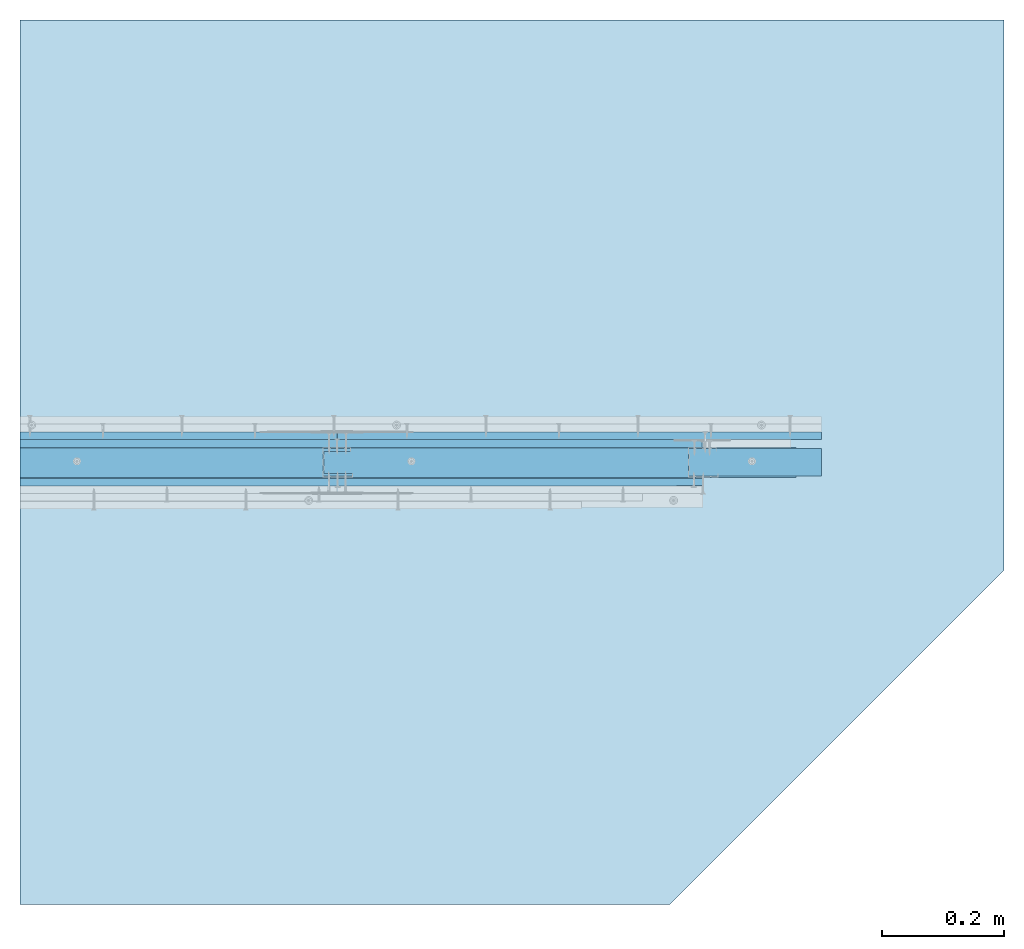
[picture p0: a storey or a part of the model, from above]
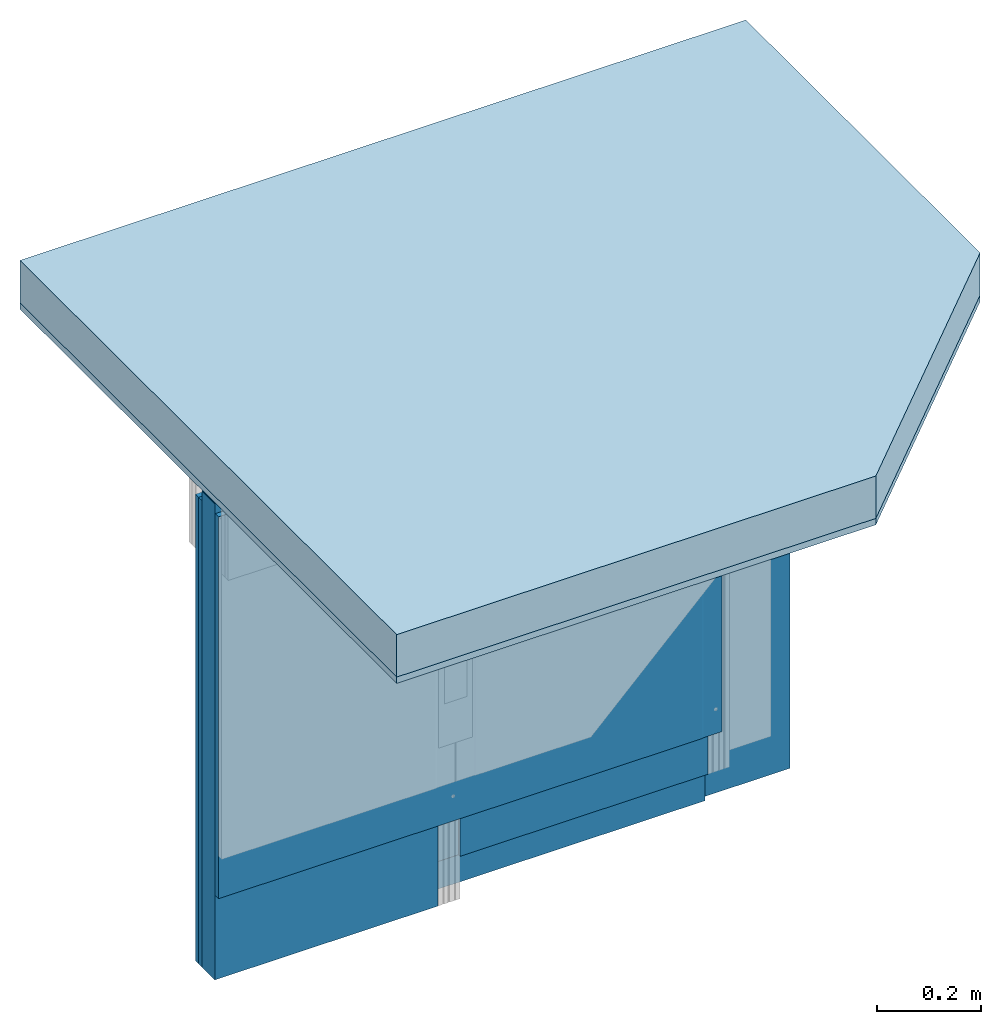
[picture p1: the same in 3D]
Properties of the parts of a building model (IFC2X3)

# File
Description: ViewDefinition [CoordinationView]
Time: 2022-01-07T10:05:12
Made in: SketchUp Pro 2015

# IfcProject, Default Project
Description: Description of Default Project

# IfcSite, Default Site
Description: Description of Default Site; RefLatitude: 24, 28, 0; RefLongitude: 54, 25, 0; RefElevation: 10 mm

# IfcBuilding, Default Building
Description: Description of Default Building

# IfcBuildingStorey, Default Building Storey
In: Default Building
Description: Description of Default Building Storey; Elevation: 0 mm

# IfcSlab (2)
In: Default Building Storey
Description: Description of Object
PredefinedType - IfcSlabTypeEnum: floor
Name
STROP
TYNK

# IfcWall (93)
In: Default Building Storey
Description: Description of Object
Name
20 x Wkręt RIGIPS TN 35
Taśma uszczelniająca piankowa RIGIPS
2 x Profil RIGIPS CW50 ULTRASTIL®
11 x Płyta gipsowo-kartonowa RIGIPS PRO (4PRO™)
16 x Kołek rozporowy min. fi 6
10 x Wkręt RIGIPS TN 25
Profil RIGIPS UW 50 ULTRASTIL®
2 x Wełna mineralna szklana lub skalna ISOVER
Dedykowana masa szpachlowa Rigips - konstrukcyjna
4 x Dedykowana masa szpachlowa Rigips - konstrukcyjna | Name - IfcLabel: Dedykowana masa szpachlowa Rigips - konstrukcyjna; Description - IfcText: Description of Object
2 x Dedykowana masa szpachlowa Rigips - wykończeniowa | Name - IfcLabel: Dedykowana masa szpachlowa Rigips - wykończeniowa; Description - IfcText: Description of Object
2 x Taśma spoinowa RIGIPS | Name - IfcLabel: Taśma spoinowa RIGIPS; Description - IfcText: Description of Object
9 x Wkręt RIGIPS TB 25
10 x Wkręt RIGIPS TB 35
2 x Kątownik
